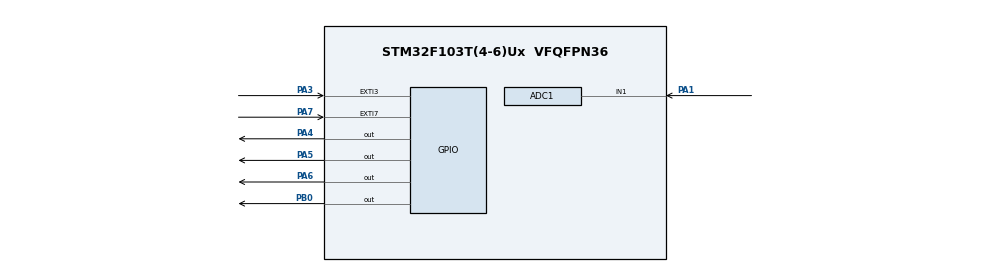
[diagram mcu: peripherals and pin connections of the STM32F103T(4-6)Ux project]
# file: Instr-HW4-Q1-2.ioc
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ADC1.Channel-1\#ChannelRegularConversion=ADC_CHANNEL_1
ADC1.NbrOfConversionFlag=1
ADC1.Rank-1\#ChannelRegularConversion=1
ADC1.SamplingTime-1\#ChannelRegularConversion=ADC_SAMPLETIME_1CYCLE_5
ADC1.master=1
Mcu.Family=STM32F1
Mcu.Name=STM32F103T(4-6)Ux
Mcu.Package=VFQFPN36
NVIC.PriorityGroup=NVIC_PRIORITYGROUP_4
PA1.Signal=ADCx_IN1
PA3.Signal=GPXTI3
PA4.Signal=GPIO_Output
PA5.Signal=GPIO_Output
PA6.Signal=GPIO_Output
PA7.Signal=GPXTI7
PB0.Signal=GPIO_Output
ProjectManager.HeapSize=0x200
ProjectManager.StackSize=0x400
ProjectManager.TargetToolchain=STM32CubeIDE
RCC.APB1Freq_Value=8000000
RCC.APB2Freq_Value=8000000
SH.ADCx_IN1.0=ADC1_IN1,IN1
VP_SYS_VS_ND.Mode=No_Debug
board=custom

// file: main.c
/* USER CODE BEGIN Header */
/**
  ******************************************************************************
  * @file           : main.c
  * @brief          : Main program body
  ******************************************************************************
  * @attention
  *
  * Copyright (c) 2026 STMicroelectronics.
  * All rights reserved.
  *
  * This software is licensed under terms that can be found in the LICENSE file
  * in the root directory of this software component.
  * If no LICENSE file comes with this software, it is provided AS-IS.
  *
  ******************************************************************************
  */
/* USER CODE END Header */
#include "main.h"
#include "lcd.h"
#include <stdio.h>

ADC_HandleTypeDef hadc1;

/* USER CODE BEGIN PV */
Lcd_PortType port[] = {GPIOA, GPIOA, GPIOA, GPIOA};
Lcd_PinType pin[] = {GPIO_PIN_3, GPIO_PIN_4, GPIO_PIN_5, GPIO_PIN_6};
Lcd_PortType rsPort = GPIOA;
Lcd_PinType rsPin = GPIO_PIN_7;
Lcd_PortType ePort = GPIOB;
Lcd_PinType ePin = GPIO_PIN_0;
Lcd_HandleTypeDef lcd;

uint32_t adcValue = 0;
float sensorVoltage = 0.0;
float r_rtd = 0.0;
float temperature = 0.0;
char lcd_line1[16];
char lcd_line2[16];
/* USER CODE END PV */

void SystemClock_Config(void);
static void MX_GPIO_Init(void);
static void MX_ADC1_Init(void);

int main(void)
{

  /* MCU Configuration--------------------------------------------------------*/

  /* Reset of all peripherals, Initializes the Flash interface and the Systick. */
  HAL_Init();

  /* Configure the system clock */
  SystemClock_Config();

  /* Initialize all configured peripherals */
  MX_GPIO_Init();
  MX_ADC1_Init();
  /* USER CODE BEGIN 2 */
  lcd = Lcd_create(port, pin, rsPort, rsPin, ePort, ePin, LCD_4_BIT_MODE);
  HAL_Delay(100);
  Lcd_init(&lcd);
  /* USER CODE END 2 */

  /* Infinite loop */
  /* USER CODE BEGIN WHILE */
  while (1)
  {
    HAL_ADC_Start(&hadc1);
    if (HAL_ADC_PollForConversion(&hadc1, 100) == HAL_OK)
    {
        adcValue = HAL_ADC_GetValue(&hadc1);

        sensorVoltage = ((float)adcValue * 5.0f) / 4095.0f;

        float v_tc_mv = sensorVoltage * 10;
        temperature = (v_tc_mv - 0.02007f) / 0.041f;

        sprintf(lcd_line1, "Va:%.2f Vt:%.1fm", sensorVoltage, v_tc_mv);
        sprintf(lcd_line2, "Temp: %.1fC", temperature);

        Lcd_clear(&lcd);
        Lcd_cursor(&lcd, 0, 0);
        Lcd_string(&lcd, lcd_line1);
        Lcd_cursor(&lcd, 1, 0);
        Lcd_string(&lcd, lcd_line2);
    }
    HAL_ADC_Stop(&hadc1);

    HAL_Delay(500);
    /* USER CODE END WHILE */

  }
}

void SystemClock_Config(void)
{
  RCC_OscInitTypeDef RCC_OscInitStruct = {0};
  RCC_ClkInitTypeDef RCC_ClkInitStruct = {0};
  RCC_PeriphCLKInitTypeDef PeriphClkInit = {0};

  /** Initializes the RCC Oscillators according to the specified parameters
  * in the RCC_OscInitTypeDef structure.
  */
  RCC_OscInitStruct.OscillatorType = RCC_OSCILLATORTYPE_HSI;
  RCC_OscInitStruct.HSIState = RCC_HSI_ON;
  RCC_OscInitStruct.HSICalibrationValue = RCC_HSICALIBRATION_DEFAULT;
  RCC_OscInitStruct.PLL.PLLState = RCC_PLL_ON;
  RCC_OscInitStruct.PLL.PLLSource = RCC_PLLSOURCE_HSI_DIV2;
  RCC_OscInitStruct.PLL.PLLMUL = RCC_PLL_MUL9;
  if (HAL_RCC_OscConfig(&RCC_OscInitStruct) != HAL_OK)
  {
    Error_Handler();
  }

  /** Initializes the CPU, AHB and APB buses clocks
  */
  RCC_ClkInitStruct.ClockType = RCC_CLOCKTYPE_HCLK|RCC_CLOCKTYPE_SYSCLK
                              |RCC_CLOCKTYPE_PCLK1|RCC_CLOCKTYPE_PCLK2;
  RCC_ClkInitStruct.SYSCLKSource = RCC_SYSCLKSOURCE_PLLCLK;
  RCC_ClkInitStruct.AHBCLKDivider = RCC_SYSCLK_DIV1;
  RCC_ClkInitStruct.APB1CLKDivider = RCC_HCLK_DIV1;
  RCC_ClkInitStruct.APB2CLKDivider = RCC_HCLK_DIV1;

  if (HAL_RCC_ClockConfig(&RCC_ClkInitStruct, FLASH_LATENCY_1) != HAL_OK)
  {
    Error_Handler();
  }
  PeriphClkInit.PeriphClockSelection = RCC_PERIPHCLK_ADC;
  PeriphClkInit.AdcClockSelection = RCC_ADCPCLK2_DIV4;
  if (HAL_RCCEx_PeriphCLKConfig(&PeriphClkInit) != HAL_OK)
  {
    Error_Handler();
  }
}

static void MX_ADC1_Init(void)
{

  ADC_ChannelConfTypeDef sConfig = {0};

  /** Common config
  */
  hadc1.Instance = ADC1;
  hadc1.Init.ScanConvMode = ADC_SCAN_DISABLE;
  hadc1.Init.ContinuousConvMode = DISABLE;
  hadc1.Init.DiscontinuousConvMode = DISABLE;
  hadc1.Init.ExternalTrigConv = ADC_SOFTWARE_START;
  hadc1.Init.DataAlign = ADC_DATAALIGN_RIGHT;
  hadc1.Init.NbrOfConversion = 1;
  if (HAL_ADC_Init(&hadc1) != HAL_OK)
  {
    Error_Handler();
  }

  /** Configure Regular Channel
  */
  sConfig.Channel = ADC_CHANNEL_1;
  sConfig.Rank = ADC_REGULAR_RANK_1;
  sConfig.SamplingTime = ADC_SAMPLETIME_1CYCLE_5;
  if (HAL_ADC_ConfigChannel(&hadc1, &sConfig) != HAL_OK)
  {
    Error_Handler();
  }

}

static void MX_GPIO_Init(void)
{
  GPIO_InitTypeDef GPIO_InitStruct = {0};

  /* GPIO Ports Clock Enable */
  __HAL_RCC_GPIOA_CLK_ENABLE();
  __HAL_RCC_GPIOB_CLK_ENABLE();

  /*Configure GPIO pin Output Level */
  HAL_GPIO_WritePin(GPIOA, GPIO_PIN_3|GPIO_PIN_4|GPIO_PIN_5|GPIO_PIN_6
                          |GPIO_PIN_7, GPIO_PIN_RESET);

  /*Configure GPIO pin Output Level */
  HAL_GPIO_WritePin(GPIOB, GPIO_PIN_0, GPIO_PIN_RESET);

  /*Configure GPIO pins : PA3 PA4 PA5 PA6
                           PA7 */
  GPIO_InitStruct.Pin = GPIO_PIN_3|GPIO_PIN_4|GPIO_PIN_5|GPIO_PIN_6
                          |GPIO_PIN_7;
  GPIO_InitStruct.Mode = GPIO_MODE_OUTPUT_PP;
  GPIO_InitStruct.Pull = GPIO_NOPULL;
  GPIO_InitStruct.Speed = GPIO_SPEED_FREQ_LOW;
  HAL_GPIO_Init(GPIOA, &GPIO_InitStruct);

  /*Configure GPIO pin : PB0 */
  GPIO_InitStruct.Pin = GPIO_PIN_0;
  GPIO_InitStruct.Mode = GPIO_MODE_OUTPUT_PP;
  GPIO_InitStruct.Pull = GPIO_NOPULL;
  GPIO_InitStruct.Speed = GPIO_SPEED_FREQ_LOW;
  HAL_GPIO_Init(GPIOB, &GPIO_InitStruct);

}

void Error_Handler(void)
{
  __disable_irq();
  while (1)
  {
  }
}
